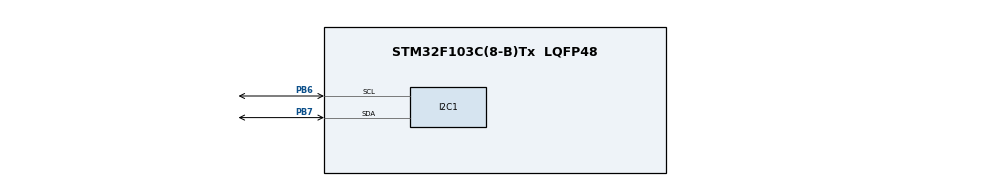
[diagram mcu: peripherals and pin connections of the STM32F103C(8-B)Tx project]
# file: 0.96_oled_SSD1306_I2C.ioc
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I2C1.I2C_Mode=I2C_Fast
Mcu.Family=STM32F1
Mcu.Name=STM32F103C(8-B)Tx
Mcu.Package=LQFP48
NVIC.PriorityGroup=NVIC_PRIORITYGROUP_4
PA13.Mode=Serial_Wire
PA13.Signal=SYS_JTMS-SWDIO
PA14.Mode=Serial_Wire
PA14.Signal=SYS_JTCK-SWCLK
PB6.Mode=I2C
PB6.Signal=I2C1_SCL
PB7.Mode=I2C
PB7.Signal=I2C1_SDA
PD0-OSC_IN.Mode=HSE-External-Oscillator
PD0-OSC_IN.Signal=RCC_OSC_IN
PD1-OSC_OUT.Mode=HSE-External-Oscillator
PD1-OSC_OUT.Signal=RCC_OSC_OUT
ProjectManager.HeapSize=0x200
ProjectManager.StackSize=0x400
ProjectManager.TargetToolchain=STM32CubeIDE
RCC.AHBFreq_Value=72000000
RCC.APB1CLKDivider=RCC_HCLK_DIV2
RCC.APB1Freq_Value=36000000
RCC.APB1TimFreq_Value=72000000
RCC.APB2Freq_Value=72000000
RCC.APB2TimFreq_Value=72000000
RCC.HCLKFreq_Value=72000000
RCC.PLLMUL=RCC_PLL_MUL9
RCC.PLLSourceVirtual=RCC_PLLSOURCE_HSE
RCC.SYSCLKFreq_VALUE=72000000
RCC.SYSCLKSource=RCC_SYSCLKSOURCE_PLLCLK
RCC.USBFreq_Value=72000000
board=custom

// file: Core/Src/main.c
/* USER CODE BEGIN Header */
/**
  ******************************************************************************
  * @file           : main.c
  * @brief          : Main program body
  ******************************************************************************
  * @attention
  *
  * Copyright (c) 2024 STMicroelectronics.
  * All rights reserved.
  *
  * This software is licensed under terms that can be found in the LICENSE file
  * in the root directory of this software component.
  * If no LICENSE file comes with this software, it is provided AS-IS.
  *
  ******************************************************************************
  */
/* USER CODE END Header */
#include "main.h"

/* USER CODE BEGIN Includes */
#include "ssd1306.h"
#include "fonts.h"
#include "stdio.h"
#include "bitmap.h"
#include "horse_anim.h"
/* USER CODE END Includes */

I2C_HandleTypeDef hi2c1;

void SystemClock_Config(void);
static void MX_GPIO_Init(void);
static void MX_I2C1_Init(void);

int main(void)
{

  /* MCU Configuration--------------------------------------------------------*/

  /* Reset of all peripherals, Initializes the Flash interface and the Systick. */
  HAL_Init();

  /* Configure the system clock */
  SystemClock_Config();

  /* Initialize all configured peripherals */
  MX_GPIO_Init();
  MX_I2C1_Init();
  /* USER CODE BEGIN 2 */

//  SSD1306_Init (); // initialise the display
//  SSD1306_GotoXY (10,10); // goto 10, 10
//  SSD1306_Puts ("HELLO", &Font_11x18, 1); // print Hello
//  SSD1306_GotoXY (10, 30);
//  SSD1306_Puts ("WORLD !!", &Font_11x18, 1);
//  SSD1306_UpdateScreen(); // update screen

//  int num = 123456; float flt = 123.45;
//  char bufnum[7]; char bufflt[7];
//  SSD1306_Init (); // initialise the display
//  sprintf (bufnum, "%d", num);
//  sprintf (bufflt, "%.2f", flt);
//  SSD1306_GotoXY (10,10); // goto 10, 10
//  SSD1306_Puts (bufnum, &Font_11x18, 1); // print Hello
//  SSD1306_GotoXY (10, 30);
//  SSD1306_Puts (bufflt, &Font_11x18, 1);
//  SSD1306_UpdateScreen(); // update screen

//  SSD1306_Init();
//  SSD1306_DrawBitmap(0, 0, logo, 128, 64, 1);
//  SSD1306_UpdateScreen(); // update screen

  SSD1306_Init();
  SSD1306_DrawBitmap(0, 0, logo, 128, 64, 1);
  SSD1306_UpdateScreen(); // update screen

  SSD1306_ScrollRight(0x00, 0x07);    // scroll entire screen (Page0 to Page7) right
  HAL_Delay (5000);
  SSD1306_Stopscroll();

  SSD1306_ScrollLeft(0x00, 0x07);    // scroll entire screen (Page0 to Page7) right
  HAL_Delay (5000);
  SSD1306_Stopscroll();

  /* USER CODE END 2 */

  /* Infinite loop */
  while (1)
  {

    /* USER CODE BEGIN 3 */
	  //// HORSE ANIMATION START //////

	  SSD1306_Clear();
	  SSD1306_DrawBitmap(0,0,horse1,128,64,1);
	  SSD1306_UpdateScreen();

	  SSD1306_Clear();
	  SSD1306_DrawBitmap(0,0,horse2,128,64,1);
	  SSD1306_UpdateScreen();

	  SSD1306_Clear();
	  SSD1306_DrawBitmap(0,0,horse3,128,64,1);
	  SSD1306_UpdateScreen();

	  SSD1306_Clear();
	  SSD1306_DrawBitmap(0,0,horse4,128,64,1);
	  SSD1306_UpdateScreen();

	  SSD1306_Clear();
	  SSD1306_DrawBitmap(0,0,horse5,128,64,1);
	  SSD1306_UpdateScreen();

	  SSD1306_Clear();
	  SSD1306_DrawBitmap(0,0,horse6,128,64,1);
	  SSD1306_UpdateScreen();

	  SSD1306_Clear();
	  SSD1306_DrawBitmap(0,0,horse7,128,64,1);
	  SSD1306_UpdateScreen();

	  SSD1306_Clear();
	  SSD1306_DrawBitmap(0,0,horse8,128,64,1);
	  SSD1306_UpdateScreen();

	  SSD1306_Clear();
	  SSD1306_DrawBitmap(0,0,horse9,128,64,1);
	  SSD1306_UpdateScreen();

	  SSD1306_Clear();
	  SSD1306_DrawBitmap(0,0,horse10,128,64,1);
	  SSD1306_UpdateScreen();

	  //// HORSE ANIMATION ENDS //////
  }
  /* USER CODE END 3 */
}

void SystemClock_Config(void)
{
  RCC_OscInitTypeDef RCC_OscInitStruct = {0};
  RCC_ClkInitTypeDef RCC_ClkInitStruct = {0};

  // Configure oscillator
  RCC_OscInitStruct.OscillatorType = RCC_OSCILLATORTYPE_HSI;
  RCC_OscInitStruct.HSIState = RCC_HSI_ON;
  RCC_OscInitStruct.HSICalibrationValue = RCC_HSICALIBRATION_DEFAULT;
  RCC_OscInitStruct.PLL.PLLState = RCC_PLL_ON;
  RCC_OscInitStruct.PLL.PLLSource = RCC_PLLSOURCE_HSI;
  RCC_OscInitStruct.PLL.PLLMUL = RCC_PLL_MUL6;    // Adjust this for your needed frequency
  if (HAL_RCC_OscConfig(&RCC_OscInitStruct) != HAL_OK)
  {
    Error_Handler();
  }

  // Configure the clock tree
  RCC_ClkInitStruct.ClockType = RCC_CLOCKTYPE_HCLK|RCC_CLOCKTYPE_SYSCLK
                              |RCC_CLOCKTYPE_PCLK1;
  RCC_ClkInitStruct.SYSCLKSource = RCC_SYSCLKSOURCE_PLLCLK;
  RCC_ClkInitStruct.AHBCLKDivider = RCC_SYSCLK_DIV1;
  RCC_ClkInitStruct.APB1CLKDivider = RCC_HCLK_DIV1;

  if (HAL_RCC_ClockConfig(&RCC_ClkInitStruct, FLASH_LATENCY_1) != HAL_OK)
  {
    Error_Handler();
  }
}

void MX_I2C1_Init(void)
{
  hi2c1.Instance = I2C1;
  hi2c1.Init.Timing = 0x2000090E;  // This timing value is for 400kHz with 48MHz clock
  hi2c1.Init.OwnAddress1 = 0;
  hi2c1.Init.AddressingMode = I2C_ADDRESSINGMODE_7BIT;
  hi2c1.Init.DualAddressMode = I2C_DUALADDRESS_DISABLE;
  hi2c1.Init.OwnAddress2 = 0;
  hi2c1.Init.OwnAddress2Masks = I2C_OA2_NOMASK;
  hi2c1.Init.GeneralCallMode = I2C_GENERALCALL_DISABLE;
  hi2c1.Init.NoStretchMode = I2C_NOSTRETCH_DISABLE;
  if (HAL_I2C_Init(&hi2c1) != HAL_OK)
  {
    Error_Handler();
  }

  if (HAL_I2CEx_ConfigAnalogFilter(&hi2c1, I2C_ANALOGFILTER_ENABLE) != HAL_OK)
  {
    Error_Handler();
  }

  if (HAL_I2CEx_ConfigDigitalFilter(&hi2c1, 0) != HAL_OK)
  {
    Error_Handler();
  }
}

static void MX_GPIO_Init(void)
{

  /* GPIO Ports Clock Enable */
  __HAL_RCC_GPIOD_CLK_ENABLE();
  __HAL_RCC_GPIOA_CLK_ENABLE();
  __HAL_RCC_GPIOB_CLK_ENABLE();

}

void Error_Handler(void)
{
  __disable_irq();
  while (1)
  {
  }
}
